VERSION 5.7 ;
  NOWIREEXTENSIONATPIN ON ;
  DIVIDERCHAR "/" ;
  BUSBITCHARS "[]" ;
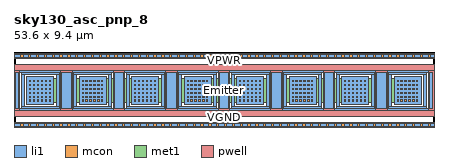
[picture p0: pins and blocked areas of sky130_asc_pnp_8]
MACRO sky130_asc_pnp_8
  CLASS CORE ;
  FOREIGN sky130_asc_pnp_8 ;
  ORIGIN 0.000 0.000 ;
  SIZE 53.600 BY 9.400 ;
  SITE unitasc ;
  PIN Emitter
    DIRECTION INOUT ;
    ANTENNADIFFAREA 92.479996 ;
    PORT
      LAYER li1 ;
        RECT 1.615 2.665 5.085 6.135 ;
        RECT 8.315 2.665 11.785 6.135 ;
        RECT 15.015 2.665 18.485 6.135 ;
        RECT 21.715 2.665 25.185 6.135 ;
        RECT 28.415 2.665 31.885 6.135 ;
        RECT 35.115 2.665 38.585 6.135 ;
        RECT 41.815 2.665 45.285 6.135 ;
        RECT 48.515 2.665 51.985 6.135 ;
      LAYER mcon ;
        RECT 1.980 5.530 2.150 5.700 ;
        RECT 2.480 5.530 2.650 5.700 ;
        RECT 2.980 5.530 3.150 5.700 ;
        RECT 3.480 5.530 3.650 5.700 ;
        RECT 3.980 5.530 4.150 5.700 ;
        RECT 4.480 5.530 4.650 5.700 ;
        RECT 1.980 5.030 2.150 5.200 ;
        RECT 2.480 5.030 2.650 5.200 ;
        RECT 2.980 5.030 3.150 5.200 ;
        RECT 3.480 5.030 3.650 5.200 ;
        RECT 3.980 5.030 4.150 5.200 ;
        RECT 4.480 5.030 4.650 5.200 ;
        RECT 1.980 4.530 2.150 4.700 ;
        RECT 2.480 4.530 2.650 4.700 ;
        RECT 2.980 4.530 3.150 4.700 ;
        RECT 3.480 4.530 3.650 4.700 ;
        RECT 3.980 4.530 4.150 4.700 ;
        RECT 4.480 4.530 4.650 4.700 ;
        RECT 1.980 4.030 2.150 4.200 ;
        RECT 2.480 4.030 2.650 4.200 ;
        RECT 2.980 4.030 3.150 4.200 ;
        RECT 3.480 4.030 3.650 4.200 ;
        RECT 3.980 4.030 4.150 4.200 ;
        RECT 4.480 4.030 4.650 4.200 ;
        RECT 1.980 3.530 2.150 3.700 ;
        RECT 2.480 3.530 2.650 3.700 ;
        RECT 2.980 3.530 3.150 3.700 ;
        RECT 3.480 3.530 3.650 3.700 ;
        RECT 3.980 3.530 4.150 3.700 ;
        RECT 4.480 3.530 4.650 3.700 ;
        RECT 1.980 3.030 2.150 3.200 ;
        RECT 2.480 3.030 2.650 3.200 ;
        RECT 2.980 3.030 3.150 3.200 ;
        RECT 3.480 3.030 3.650 3.200 ;
        RECT 3.980 3.030 4.150 3.200 ;
        RECT 4.480 3.030 4.650 3.200 ;
        RECT 8.680 5.530 8.850 5.700 ;
        RECT 9.180 5.530 9.350 5.700 ;
        RECT 9.680 5.530 9.850 5.700 ;
        RECT 10.180 5.530 10.350 5.700 ;
        RECT 10.680 5.530 10.850 5.700 ;
        RECT 11.180 5.530 11.350 5.700 ;
        RECT 8.680 5.030 8.850 5.200 ;
        RECT 9.180 5.030 9.350 5.200 ;
        RECT 9.680 5.030 9.850 5.200 ;
        RECT 10.180 5.030 10.350 5.200 ;
        RECT 10.680 5.030 10.850 5.200 ;
        RECT 11.180 5.030 11.350 5.200 ;
        RECT 8.680 4.530 8.850 4.700 ;
        RECT 9.180 4.530 9.350 4.700 ;
        RECT 9.680 4.530 9.850 4.700 ;
        RECT 10.180 4.530 10.350 4.700 ;
        RECT 10.680 4.530 10.850 4.700 ;
        RECT 11.180 4.530 11.350 4.700 ;
        RECT 8.680 4.030 8.850 4.200 ;
        RECT 9.180 4.030 9.350 4.200 ;
        RECT 9.680 4.030 9.850 4.200 ;
        RECT 10.180 4.030 10.350 4.200 ;
        RECT 10.680 4.030 10.850 4.200 ;
        RECT 11.180 4.030 11.350 4.200 ;
        RECT 8.680 3.530 8.850 3.700 ;
        RECT 9.180 3.530 9.350 3.700 ;
        RECT 9.680 3.530 9.850 3.700 ;
        RECT 10.180 3.530 10.350 3.700 ;
        RECT 10.680 3.530 10.850 3.700 ;
        RECT 11.180 3.530 11.350 3.700 ;
        RECT 8.680 3.030 8.850 3.200 ;
        RECT 9.180 3.030 9.350 3.200 ;
        RECT 9.680 3.030 9.850 3.200 ;
        RECT 10.180 3.030 10.350 3.200 ;
        RECT 10.680 3.030 10.850 3.200 ;
        RECT 11.180 3.030 11.350 3.200 ;
        RECT 15.380 5.530 15.550 5.700 ;
        RECT 15.880 5.530 16.050 5.700 ;
        RECT 16.380 5.530 16.550 5.700 ;
        RECT 16.880 5.530 17.050 5.700 ;
        RECT 17.380 5.530 17.550 5.700 ;
        RECT 17.880 5.530 18.050 5.700 ;
        RECT 15.380 5.030 15.550 5.200 ;
        RECT 15.880 5.030 16.050 5.200 ;
        RECT 16.380 5.030 16.550 5.200 ;
        RECT 16.880 5.030 17.050 5.200 ;
        RECT 17.380 5.030 17.550 5.200 ;
        RECT 17.880 5.030 18.050 5.200 ;
        RECT 15.380 4.530 15.550 4.700 ;
        RECT 15.880 4.530 16.050 4.700 ;
        RECT 16.380 4.530 16.550 4.700 ;
        RECT 16.880 4.530 17.050 4.700 ;
        RECT 17.380 4.530 17.550 4.700 ;
        RECT 17.880 4.530 18.050 4.700 ;
        RECT 15.380 4.030 15.550 4.200 ;
        RECT 15.880 4.030 16.050 4.200 ;
        RECT 16.380 4.030 16.550 4.200 ;
        RECT 16.880 4.030 17.050 4.200 ;
        RECT 17.380 4.030 17.550 4.200 ;
        RECT 17.880 4.030 18.050 4.200 ;
        RECT 15.380 3.530 15.550 3.700 ;
        RECT 15.880 3.530 16.050 3.700 ;
        RECT 16.380 3.530 16.550 3.700 ;
        RECT 16.880 3.530 17.050 3.700 ;
        RECT 17.380 3.530 17.550 3.700 ;
        RECT 17.880 3.530 18.050 3.700 ;
        RECT 15.380 3.030 15.550 3.200 ;
        RECT 15.880 3.030 16.050 3.200 ;
        RECT 16.380 3.030 16.550 3.200 ;
        RECT 16.880 3.030 17.050 3.200 ;
        RECT 17.380 3.030 17.550 3.200 ;
        RECT 17.880 3.030 18.050 3.200 ;
        RECT 22.080 5.530 22.250 5.700 ;
        RECT 22.580 5.530 22.750 5.700 ;
        RECT 23.080 5.530 23.250 5.700 ;
        RECT 23.580 5.530 23.750 5.700 ;
        RECT 24.080 5.530 24.250 5.700 ;
        RECT 24.580 5.530 24.750 5.700 ;
        RECT 22.080 5.030 22.250 5.200 ;
        RECT 22.580 5.030 22.750 5.200 ;
        RECT 23.080 5.030 23.250 5.200 ;
        RECT 23.580 5.030 23.750 5.200 ;
        RECT 24.080 5.030 24.250 5.200 ;
        RECT 24.580 5.030 24.750 5.200 ;
        RECT 22.080 4.530 22.250 4.700 ;
        RECT 22.580 4.530 22.750 4.700 ;
        RECT 23.080 4.530 23.250 4.700 ;
        RECT 23.580 4.530 23.750 4.700 ;
        RECT 24.080 4.530 24.250 4.700 ;
        RECT 24.580 4.530 24.750 4.700 ;
        RECT 22.080 4.030 22.250 4.200 ;
        RECT 22.580 4.030 22.750 4.200 ;
        RECT 23.080 4.030 23.250 4.200 ;
        RECT 23.580 4.030 23.750 4.200 ;
        RECT 24.080 4.030 24.250 4.200 ;
        RECT 24.580 4.030 24.750 4.200 ;
        RECT 22.080 3.530 22.250 3.700 ;
        RECT 22.580 3.530 22.750 3.700 ;
        RECT 23.080 3.530 23.250 3.700 ;
        RECT 23.580 3.530 23.750 3.700 ;
        RECT 24.080 3.530 24.250 3.700 ;
        RECT 24.580 3.530 24.750 3.700 ;
        RECT 22.080 3.030 22.250 3.200 ;
        RECT 22.580 3.030 22.750 3.200 ;
        RECT 23.080 3.030 23.250 3.200 ;
        RECT 23.580 3.030 23.750 3.200 ;
        RECT 24.080 3.030 24.250 3.200 ;
        RECT 24.580 3.030 24.750 3.200 ;
        RECT 28.780 5.530 28.950 5.700 ;
        RECT 29.280 5.530 29.450 5.700 ;
        RECT 29.780 5.530 29.950 5.700 ;
        RECT 30.280 5.530 30.450 5.700 ;
        RECT 30.780 5.530 30.950 5.700 ;
        RECT 31.280 5.530 31.450 5.700 ;
        RECT 28.780 5.030 28.950 5.200 ;
        RECT 29.280 5.030 29.450 5.200 ;
        RECT 29.780 5.030 29.950 5.200 ;
        RECT 30.280 5.030 30.450 5.200 ;
        RECT 30.780 5.030 30.950 5.200 ;
        RECT 31.280 5.030 31.450 5.200 ;
        RECT 28.780 4.530 28.950 4.700 ;
        RECT 29.280 4.530 29.450 4.700 ;
        RECT 29.780 4.530 29.950 4.700 ;
        RECT 30.280 4.530 30.450 4.700 ;
        RECT 30.780 4.530 30.950 4.700 ;
        RECT 31.280 4.530 31.450 4.700 ;
        RECT 28.780 4.030 28.950 4.200 ;
        RECT 29.280 4.030 29.450 4.200 ;
        RECT 29.780 4.030 29.950 4.200 ;
        RECT 30.280 4.030 30.450 4.200 ;
        RECT 30.780 4.030 30.950 4.200 ;
        RECT 31.280 4.030 31.450 4.200 ;
        RECT 28.780 3.530 28.950 3.700 ;
        RECT 29.280 3.530 29.450 3.700 ;
        RECT 29.780 3.530 29.950 3.700 ;
        RECT 30.280 3.530 30.450 3.700 ;
        RECT 30.780 3.530 30.950 3.700 ;
        RECT 31.280 3.530 31.450 3.700 ;
        RECT 28.780 3.030 28.950 3.200 ;
        RECT 29.280 3.030 29.450 3.200 ;
        RECT 29.780 3.030 29.950 3.200 ;
        RECT 30.280 3.030 30.450 3.200 ;
        RECT 30.780 3.030 30.950 3.200 ;
        RECT 31.280 3.030 31.450 3.200 ;
        RECT 35.480 5.530 35.650 5.700 ;
        RECT 35.980 5.530 36.150 5.700 ;
        RECT 36.480 5.530 36.650 5.700 ;
        RECT 36.980 5.530 37.150 5.700 ;
        RECT 37.480 5.530 37.650 5.700 ;
        RECT 37.980 5.530 38.150 5.700 ;
        RECT 35.480 5.030 35.650 5.200 ;
        RECT 35.980 5.030 36.150 5.200 ;
        RECT 36.480 5.030 36.650 5.200 ;
        RECT 36.980 5.030 37.150 5.200 ;
        RECT 37.480 5.030 37.650 5.200 ;
        RECT 37.980 5.030 38.150 5.200 ;
        RECT 35.480 4.530 35.650 4.700 ;
        RECT 35.980 4.530 36.150 4.700 ;
        RECT 36.480 4.530 36.650 4.700 ;
        RECT 36.980 4.530 37.150 4.700 ;
        RECT 37.480 4.530 37.650 4.700 ;
        RECT 37.980 4.530 38.150 4.700 ;
        RECT 35.480 4.030 35.650 4.200 ;
        RECT 35.980 4.030 36.150 4.200 ;
        RECT 36.480 4.030 36.650 4.200 ;
        RECT 36.980 4.030 37.150 4.200 ;
        RECT 37.480 4.030 37.650 4.200 ;
        RECT 37.980 4.030 38.150 4.200 ;
        RECT 35.480 3.530 35.650 3.700 ;
        RECT 35.980 3.530 36.150 3.700 ;
        RECT 36.480 3.530 36.650 3.700 ;
        RECT 36.980 3.530 37.150 3.700 ;
        RECT 37.480 3.530 37.650 3.700 ;
        RECT 37.980 3.530 38.150 3.700 ;
        RECT 35.480 3.030 35.650 3.200 ;
        RECT 35.980 3.030 36.150 3.200 ;
        RECT 36.480 3.030 36.650 3.200 ;
        RECT 36.980 3.030 37.150 3.200 ;
        RECT 37.480 3.030 37.650 3.200 ;
        RECT 37.980 3.030 38.150 3.200 ;
        RECT 42.180 5.530 42.350 5.700 ;
        RECT 42.680 5.530 42.850 5.700 ;
        RECT 43.180 5.530 43.350 5.700 ;
        RECT 43.680 5.530 43.850 5.700 ;
        RECT 44.180 5.530 44.350 5.700 ;
        RECT 44.680 5.530 44.850 5.700 ;
        RECT 42.180 5.030 42.350 5.200 ;
        RECT 42.680 5.030 42.850 5.200 ;
        RECT 43.180 5.030 43.350 5.200 ;
        RECT 43.680 5.030 43.850 5.200 ;
        RECT 44.180 5.030 44.350 5.200 ;
        RECT 44.680 5.030 44.850 5.200 ;
        RECT 42.180 4.530 42.350 4.700 ;
        RECT 42.680 4.530 42.850 4.700 ;
        RECT 43.180 4.530 43.350 4.700 ;
        RECT 43.680 4.530 43.850 4.700 ;
        RECT 44.180 4.530 44.350 4.700 ;
        RECT 44.680 4.530 44.850 4.700 ;
        RECT 42.180 4.030 42.350 4.200 ;
        RECT 42.680 4.030 42.850 4.200 ;
        RECT 43.180 4.030 43.350 4.200 ;
        RECT 43.680 4.030 43.850 4.200 ;
        RECT 44.180 4.030 44.350 4.200 ;
        RECT 44.680 4.030 44.850 4.200 ;
        RECT 42.180 3.530 42.350 3.700 ;
        RECT 42.680 3.530 42.850 3.700 ;
        RECT 43.180 3.530 43.350 3.700 ;
        RECT 43.680 3.530 43.850 3.700 ;
        RECT 44.180 3.530 44.350 3.700 ;
        RECT 44.680 3.530 44.850 3.700 ;
        RECT 42.180 3.030 42.350 3.200 ;
        RECT 42.680 3.030 42.850 3.200 ;
        RECT 43.180 3.030 43.350 3.200 ;
        RECT 43.680 3.030 43.850 3.200 ;
        RECT 44.180 3.030 44.350 3.200 ;
        RECT 44.680 3.030 44.850 3.200 ;
        RECT 48.880 5.530 49.050 5.700 ;
        RECT 49.380 5.530 49.550 5.700 ;
        RECT 49.880 5.530 50.050 5.700 ;
        RECT 50.380 5.530 50.550 5.700 ;
        RECT 50.880 5.530 51.050 5.700 ;
        RECT 51.380 5.530 51.550 5.700 ;
        RECT 48.880 5.030 49.050 5.200 ;
        RECT 49.380 5.030 49.550 5.200 ;
        RECT 49.880 5.030 50.050 5.200 ;
        RECT 50.380 5.030 50.550 5.200 ;
        RECT 50.880 5.030 51.050 5.200 ;
        RECT 51.380 5.030 51.550 5.200 ;
        RECT 48.880 4.530 49.050 4.700 ;
        RECT 49.380 4.530 49.550 4.700 ;
        RECT 49.880 4.530 50.050 4.700 ;
        RECT 50.380 4.530 50.550 4.700 ;
        RECT 50.880 4.530 51.050 4.700 ;
        RECT 51.380 4.530 51.550 4.700 ;
        RECT 48.880 4.030 49.050 4.200 ;
        RECT 49.380 4.030 49.550 4.200 ;
        RECT 49.880 4.030 50.050 4.200 ;
        RECT 50.380 4.030 50.550 4.200 ;
        RECT 50.880 4.030 51.050 4.200 ;
        RECT 51.380 4.030 51.550 4.200 ;
        RECT 48.880 3.530 49.050 3.700 ;
        RECT 49.380 3.530 49.550 3.700 ;
        RECT 49.880 3.530 50.050 3.700 ;
        RECT 50.380 3.530 50.550 3.700 ;
        RECT 50.880 3.530 51.050 3.700 ;
        RECT 51.380 3.530 51.550 3.700 ;
        RECT 48.880 3.030 49.050 3.200 ;
        RECT 49.380 3.030 49.550 3.200 ;
        RECT 49.880 3.030 50.050 3.200 ;
        RECT 50.380 3.030 50.550 3.200 ;
        RECT 50.880 3.030 51.050 3.200 ;
        RECT 51.380 3.030 51.550 3.200 ;
      LAYER met1 ;
        RECT 1.820 2.870 51.780 5.930 ;
    END
  END Emitter
  PIN Base
    DIRECTION INOUT ;
    ANTENNAGATEAREA 213.831192 ;
    ANTENNADIFFAREA 158.894394 ;
    PORT
      LAYER pwell ;
        RECT 0.000 6.985 53.600 7.750 ;
        RECT 0.000 1.815 0.765 6.985 ;
        RECT 5.935 1.815 7.465 6.985 ;
        RECT 12.635 1.815 14.165 6.985 ;
        RECT 19.335 1.815 20.865 6.985 ;
        RECT 26.035 1.815 27.565 6.985 ;
        RECT 32.735 1.815 34.265 6.985 ;
        RECT 39.435 1.815 40.965 6.985 ;
        RECT 46.135 1.815 47.665 6.985 ;
        RECT 52.835 1.815 53.600 6.985 ;
        RECT 0.000 1.050 53.600 1.815 ;
      LAYER li1 ;
        RECT 0.130 6.750 53.470 7.620 ;
        RECT 0.130 2.050 0.625 6.750 ;
        RECT 0.945 6.445 5.755 6.750 ;
        RECT 0.945 2.355 1.305 6.445 ;
        RECT 5.395 2.355 5.755 6.445 ;
        RECT 0.945 2.050 5.755 2.355 ;
        RECT 6.075 2.050 7.325 6.750 ;
        RECT 7.645 6.445 12.455 6.750 ;
        RECT 7.645 2.355 8.005 6.445 ;
        RECT 12.095 2.355 12.455 6.445 ;
        RECT 7.645 2.050 12.455 2.355 ;
        RECT 12.775 2.050 14.025 6.750 ;
        RECT 14.345 6.445 19.155 6.750 ;
        RECT 14.345 2.355 14.705 6.445 ;
        RECT 18.795 2.355 19.155 6.445 ;
        RECT 14.345 2.050 19.155 2.355 ;
        RECT 19.475 2.050 20.725 6.750 ;
        RECT 21.045 6.445 25.855 6.750 ;
        RECT 21.045 2.355 21.405 6.445 ;
        RECT 25.495 2.355 25.855 6.445 ;
        RECT 21.045 2.050 25.855 2.355 ;
        RECT 26.175 2.050 27.425 6.750 ;
        RECT 27.745 6.445 32.555 6.750 ;
        RECT 27.745 2.355 28.105 6.445 ;
        RECT 32.195 2.355 32.555 6.445 ;
        RECT 27.745 2.050 32.555 2.355 ;
        RECT 32.875 2.050 34.125 6.750 ;
        RECT 34.445 6.445 39.255 6.750 ;
        RECT 34.445 2.355 34.805 6.445 ;
        RECT 38.895 2.355 39.255 6.445 ;
        RECT 34.445 2.050 39.255 2.355 ;
        RECT 39.575 2.050 40.825 6.750 ;
        RECT 41.145 6.445 45.955 6.750 ;
        RECT 41.145 2.355 41.505 6.445 ;
        RECT 45.595 2.355 45.955 6.445 ;
        RECT 41.145 2.050 45.955 2.355 ;
        RECT 46.275 2.050 47.525 6.750 ;
        RECT 47.845 6.445 52.655 6.750 ;
        RECT 47.845 2.355 48.205 6.445 ;
        RECT 52.295 2.355 52.655 6.445 ;
        RECT 47.845 2.050 52.655 2.355 ;
        RECT 52.975 2.050 53.470 6.750 ;
        RECT 0.130 1.180 53.470 2.050 ;
    END
  END Base
  PIN VPWR
    DIRECTION INOUT ;
    USE POWER ;
    PORT
      LAYER li1 ;
        RECT 0.000 8.650 53.600 8.950 ;
      LAYER mcon ;
        RECT 0.850 8.650 1.150 8.950 ;
        RECT 1.850 8.650 2.150 8.950 ;
        RECT 2.850 8.650 3.150 8.950 ;
        RECT 3.850 8.650 4.150 8.950 ;
        RECT 4.850 8.650 5.150 8.950 ;
        RECT 5.850 8.650 6.150 8.950 ;
        RECT 6.850 8.650 7.150 8.950 ;
        RECT 7.850 8.650 8.150 8.950 ;
        RECT 8.850 8.650 9.150 8.950 ;
        RECT 9.850 8.650 10.150 8.950 ;
        RECT 10.850 8.650 11.150 8.950 ;
        RECT 11.850 8.650 12.150 8.950 ;
        RECT 12.850 8.650 13.150 8.950 ;
        RECT 13.850 8.650 14.150 8.950 ;
        RECT 14.850 8.650 15.150 8.950 ;
        RECT 15.850 8.650 16.150 8.950 ;
        RECT 16.850 8.650 17.150 8.950 ;
        RECT 17.850 8.650 18.150 8.950 ;
        RECT 18.850 8.650 19.150 8.950 ;
        RECT 19.850 8.650 20.150 8.950 ;
        RECT 20.850 8.650 21.150 8.950 ;
        RECT 21.850 8.650 22.150 8.950 ;
        RECT 22.850 8.650 23.150 8.950 ;
        RECT 23.850 8.650 24.150 8.950 ;
        RECT 24.850 8.650 25.150 8.950 ;
        RECT 25.850 8.650 26.150 8.950 ;
        RECT 26.850 8.650 27.150 8.950 ;
        RECT 27.850 8.650 28.150 8.950 ;
        RECT 28.850 8.650 29.150 8.950 ;
        RECT 29.850 8.650 30.150 8.950 ;
        RECT 30.850 8.650 31.150 8.950 ;
        RECT 31.850 8.650 32.150 8.950 ;
        RECT 32.850 8.650 33.150 8.950 ;
        RECT 33.850 8.650 34.150 8.950 ;
        RECT 34.850 8.650 35.150 8.950 ;
        RECT 35.850 8.650 36.150 8.950 ;
        RECT 36.850 8.650 37.150 8.950 ;
        RECT 37.850 8.650 38.150 8.950 ;
        RECT 38.850 8.650 39.150 8.950 ;
        RECT 39.850 8.650 40.150 8.950 ;
        RECT 40.850 8.650 41.150 8.950 ;
        RECT 41.850 8.650 42.150 8.950 ;
        RECT 42.850 8.650 43.150 8.950 ;
        RECT 43.850 8.650 44.150 8.950 ;
        RECT 44.850 8.650 45.150 8.950 ;
        RECT 45.850 8.650 46.150 8.950 ;
        RECT 46.850 8.650 47.150 8.950 ;
        RECT 47.850 8.650 48.150 8.950 ;
        RECT 48.850 8.650 49.150 8.950 ;
        RECT 49.850 8.650 50.150 8.950 ;
        RECT 50.850 8.650 51.150 8.950 ;
        RECT 51.850 8.650 52.150 8.950 ;
        RECT 52.850 8.650 53.150 8.950 ;
      LAYER met1 ;
        RECT 0.000 8.500 53.600 9.100 ;
    END
  END VPWR
  PIN VGND
    DIRECTION INOUT ;
    USE GROUND ;
    PORT
      LAYER li1 ;
        RECT 0.000 -0.150 53.600 0.150 ;
      LAYER mcon ;
        RECT 0.850 -0.150 1.150 0.150 ;
        RECT 1.850 -0.150 2.150 0.150 ;
        RECT 2.850 -0.150 3.150 0.150 ;
        RECT 3.850 -0.150 4.150 0.150 ;
        RECT 4.850 -0.150 5.150 0.150 ;
        RECT 5.850 -0.150 6.150 0.150 ;
        RECT 6.850 -0.150 7.150 0.150 ;
        RECT 7.850 -0.150 8.150 0.150 ;
        RECT 8.850 -0.150 9.150 0.150 ;
        RECT 9.850 -0.150 10.150 0.150 ;
        RECT 10.850 -0.150 11.150 0.150 ;
        RECT 11.850 -0.150 12.150 0.150 ;
        RECT 12.850 -0.150 13.150 0.150 ;
        RECT 13.850 -0.150 14.150 0.150 ;
        RECT 14.850 -0.150 15.150 0.150 ;
        RECT 15.850 -0.150 16.150 0.150 ;
        RECT 16.850 -0.150 17.150 0.150 ;
        RECT 17.850 -0.150 18.150 0.150 ;
        RECT 18.850 -0.150 19.150 0.150 ;
        RECT 19.850 -0.150 20.150 0.150 ;
        RECT 20.850 -0.150 21.150 0.150 ;
        RECT 21.850 -0.150 22.150 0.150 ;
        RECT 22.850 -0.150 23.150 0.150 ;
        RECT 23.850 -0.150 24.150 0.150 ;
        RECT 24.850 -0.150 25.150 0.150 ;
        RECT 25.850 -0.150 26.150 0.150 ;
        RECT 26.850 -0.150 27.150 0.150 ;
        RECT 27.850 -0.150 28.150 0.150 ;
        RECT 28.850 -0.150 29.150 0.150 ;
        RECT 29.850 -0.150 30.150 0.150 ;
        RECT 30.850 -0.150 31.150 0.150 ;
        RECT 31.850 -0.150 32.150 0.150 ;
        RECT 32.850 -0.150 33.150 0.150 ;
        RECT 33.850 -0.150 34.150 0.150 ;
        RECT 34.850 -0.150 35.150 0.150 ;
        RECT 35.850 -0.150 36.150 0.150 ;
        RECT 36.850 -0.150 37.150 0.150 ;
        RECT 37.850 -0.150 38.150 0.150 ;
        RECT 38.850 -0.150 39.150 0.150 ;
        RECT 39.850 -0.150 40.150 0.150 ;
        RECT 40.850 -0.150 41.150 0.150 ;
        RECT 41.850 -0.150 42.150 0.150 ;
        RECT 42.850 -0.150 43.150 0.150 ;
        RECT 43.850 -0.150 44.150 0.150 ;
        RECT 44.850 -0.150 45.150 0.150 ;
        RECT 45.850 -0.150 46.150 0.150 ;
        RECT 46.850 -0.150 47.150 0.150 ;
        RECT 47.850 -0.150 48.150 0.150 ;
        RECT 48.850 -0.150 49.150 0.150 ;
        RECT 49.850 -0.150 50.150 0.150 ;
        RECT 50.850 -0.150 51.150 0.150 ;
        RECT 51.850 -0.150 52.150 0.150 ;
        RECT 52.850 -0.150 53.150 0.150 ;
      LAYER met1 ;
        RECT 0.000 -0.300 53.600 0.300 ;
    END
  END VGND
END sky130_asc_pnp_8
END LIBRARY

